##
## LEF for PtnCells ;
## created by Innovus v15.23-s045_1 on Mon Mar  9 14:37:24 2026
##

VERSION 5.8 ;

BUSBITCHARS "[]" ;
DIVIDERCHAR "/" ;

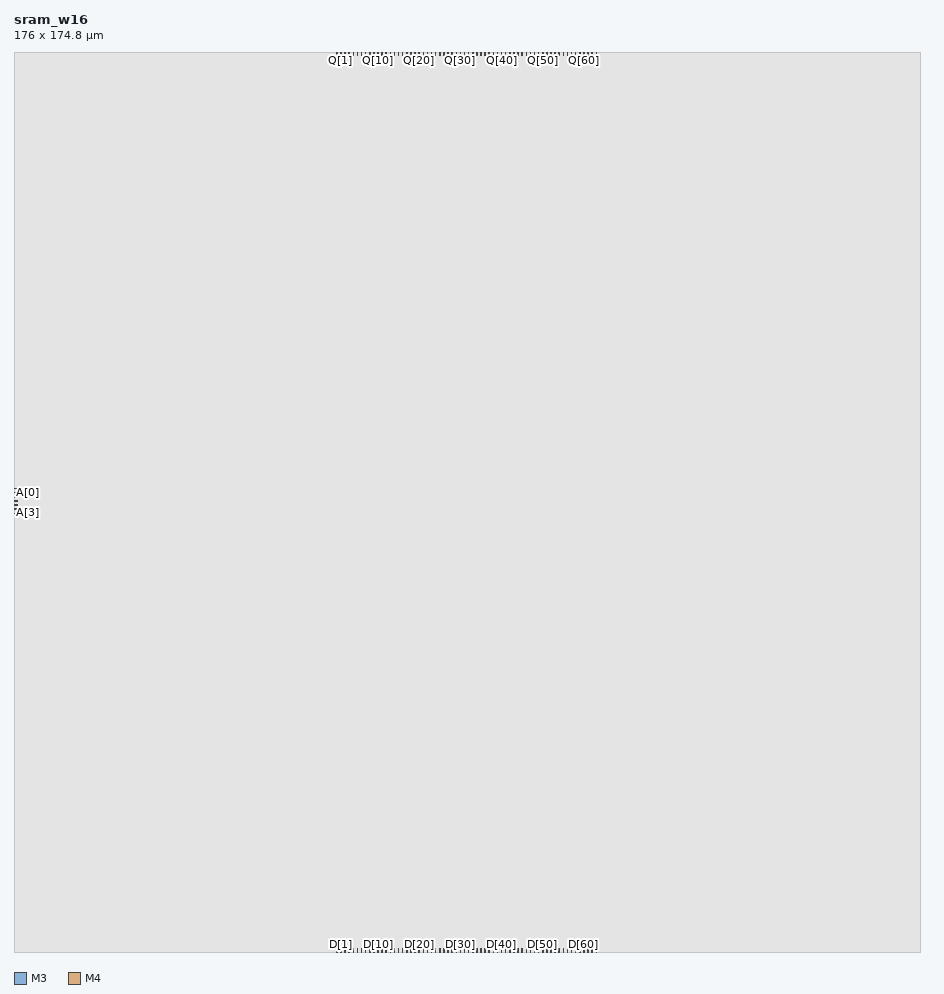
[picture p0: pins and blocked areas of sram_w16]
MACRO sram_w16
  CLASS BLOCK ;
  SIZE 176.0000 BY 174.8000 ;
  FOREIGN sram_w16 0.0000 0.0000 ;
  ORIGIN 0 0 ;
  SYMMETRY X Y R90 ;
  PIN CLK
    DIRECTION INPUT ;
    USE SIGNAL ;
    PORT
      LAYER M3 ;
        RECT 0.0000 85.1500 0.6000 85.2500 ;
    END
  END CLK
  PIN D[63]
    DIRECTION INPUT ;
    USE SIGNAL ;
    PORT
      LAYER M4 ;
        RECT 113.0500 0.0000 113.1500 0.6000 ;
    END
  END D[63]
  PIN D[62]
    DIRECTION INPUT ;
    USE SIGNAL ;
    PORT
      LAYER M4 ;
        RECT 112.2500 0.0000 112.3500 0.6000 ;
    END
  END D[62]
  PIN D[61]
    DIRECTION INPUT ;
    USE SIGNAL ;
    PORT
      LAYER M4 ;
        RECT 111.4500 0.0000 111.5500 0.6000 ;
    END
  END D[61]
  PIN D[60]
    DIRECTION INPUT ;
    USE SIGNAL ;
    PORT
      LAYER M4 ;
        RECT 110.6500 0.0000 110.7500 0.6000 ;
    END
  END D[60]
  PIN D[59]
    DIRECTION INPUT ;
    USE SIGNAL ;
    PORT
      LAYER M4 ;
        RECT 109.8500 0.0000 109.9500 0.6000 ;
    END
  END D[59]
  PIN D[58]
    DIRECTION INPUT ;
    USE SIGNAL ;
    PORT
      LAYER M4 ;
        RECT 109.0500 0.0000 109.1500 0.6000 ;
    END
  END D[58]
  PIN D[57]
    DIRECTION INPUT ;
    USE SIGNAL ;
    PORT
      LAYER M4 ;
        RECT 108.2500 0.0000 108.3500 0.6000 ;
    END
  END D[57]
  PIN D[56]
    DIRECTION INPUT ;
    USE SIGNAL ;
    PORT
      LAYER M4 ;
        RECT 107.4500 0.0000 107.5500 0.6000 ;
    END
  END D[56]
  PIN D[55]
    DIRECTION INPUT ;
    USE SIGNAL ;
    PORT
      LAYER M4 ;
        RECT 106.6500 0.0000 106.7500 0.6000 ;
    END
  END D[55]
  PIN D[54]
    DIRECTION INPUT ;
    USE SIGNAL ;
    PORT
      LAYER M4 ;
        RECT 105.8500 0.0000 105.9500 0.6000 ;
    END
  END D[54]
  PIN D[53]
    DIRECTION INPUT ;
    USE SIGNAL ;
    PORT
      LAYER M4 ;
        RECT 105.0500 0.0000 105.1500 0.6000 ;
    END
  END D[53]
  PIN D[52]
    DIRECTION INPUT ;
    USE SIGNAL ;
    PORT
      LAYER M4 ;
        RECT 104.2500 0.0000 104.3500 0.6000 ;
    END
  END D[52]
  PIN D[51]
    DIRECTION INPUT ;
    USE SIGNAL ;
    PORT
      LAYER M4 ;
        RECT 103.4500 0.0000 103.5500 0.6000 ;
    END
  END D[51]
  PIN D[50]
    DIRECTION INPUT ;
    USE SIGNAL ;
    PORT
      LAYER M4 ;
        RECT 102.6500 0.0000 102.7500 0.6000 ;
    END
  END D[50]
  PIN D[49]
    DIRECTION INPUT ;
    USE SIGNAL ;
    PORT
      LAYER M4 ;
        RECT 101.8500 0.0000 101.9500 0.6000 ;
    END
  END D[49]
  PIN D[48]
    DIRECTION INPUT ;
    USE SIGNAL ;
    PORT
      LAYER M4 ;
        RECT 101.0500 0.0000 101.1500 0.6000 ;
    END
  END D[48]
  PIN D[47]
    DIRECTION INPUT ;
    USE SIGNAL ;
    PORT
      LAYER M4 ;
        RECT 100.2500 0.0000 100.3500 0.6000 ;
    END
  END D[47]
  PIN D[46]
    DIRECTION INPUT ;
    USE SIGNAL ;
    PORT
      LAYER M4 ;
        RECT 99.4500 0.0000 99.5500 0.6000 ;
    END
  END D[46]
  PIN D[45]
    DIRECTION INPUT ;
    USE SIGNAL ;
    PORT
      LAYER M4 ;
        RECT 98.6500 0.0000 98.7500 0.6000 ;
    END
  END D[45]
  PIN D[44]
    DIRECTION INPUT ;
    USE SIGNAL ;
    PORT
      LAYER M4 ;
        RECT 97.8500 0.0000 97.9500 0.6000 ;
    END
  END D[44]
  PIN D[43]
    DIRECTION INPUT ;
    USE SIGNAL ;
    PORT
      LAYER M4 ;
        RECT 97.0500 0.0000 97.1500 0.6000 ;
    END
  END D[43]
  PIN D[42]
    DIRECTION INPUT ;
    USE SIGNAL ;
    PORT
      LAYER M4 ;
        RECT 96.2500 0.0000 96.3500 0.6000 ;
    END
  END D[42]
  PIN D[41]
    DIRECTION INPUT ;
    USE SIGNAL ;
    PORT
      LAYER M4 ;
        RECT 95.4500 0.0000 95.5500 0.6000 ;
    END
  END D[41]
  PIN D[40]
    DIRECTION INPUT ;
    USE SIGNAL ;
    PORT
      LAYER M4 ;
        RECT 94.6500 0.0000 94.7500 0.6000 ;
    END
  END D[40]
  PIN D[39]
    DIRECTION INPUT ;
    USE SIGNAL ;
    PORT
      LAYER M4 ;
        RECT 93.8500 0.0000 93.9500 0.6000 ;
    END
  END D[39]
  PIN D[38]
    DIRECTION INPUT ;
    USE SIGNAL ;
    PORT
      LAYER M4 ;
        RECT 93.0500 0.0000 93.1500 0.6000 ;
    END
  END D[38]
  PIN D[37]
    DIRECTION INPUT ;
    USE SIGNAL ;
    PORT
      LAYER M4 ;
        RECT 92.2500 0.0000 92.3500 0.6000 ;
    END
  END D[37]
  PIN D[36]
    DIRECTION INPUT ;
    USE SIGNAL ;
    PORT
      LAYER M4 ;
        RECT 91.4500 0.0000 91.5500 0.6000 ;
    END
  END D[36]
  PIN D[35]
    DIRECTION INPUT ;
    USE SIGNAL ;
    PORT
      LAYER M4 ;
        RECT 90.6500 0.0000 90.7500 0.6000 ;
    END
  END D[35]
  PIN D[34]
    DIRECTION INPUT ;
    USE SIGNAL ;
    PORT
      LAYER M4 ;
        RECT 89.8500 0.0000 89.9500 0.6000 ;
    END
  END D[34]
  PIN D[33]
    DIRECTION INPUT ;
    USE SIGNAL ;
    PORT
      LAYER M4 ;
        RECT 89.0500 0.0000 89.1500 0.6000 ;
    END
  END D[33]
  PIN D[32]
    DIRECTION INPUT ;
    USE SIGNAL ;
    PORT
      LAYER M4 ;
        RECT 88.2500 0.0000 88.3500 0.6000 ;
    END
  END D[32]
  PIN D[31]
    DIRECTION INPUT ;
    USE SIGNAL ;
    PORT
      LAYER M4 ;
        RECT 87.4500 0.0000 87.5500 0.6000 ;
    END
  END D[31]
  PIN D[30]
    DIRECTION INPUT ;
    USE SIGNAL ;
    PORT
      LAYER M4 ;
        RECT 86.6500 0.0000 86.7500 0.6000 ;
    END
  END D[30]
  PIN D[29]
    DIRECTION INPUT ;
    USE SIGNAL ;
    PORT
      LAYER M4 ;
        RECT 85.8500 0.0000 85.9500 0.6000 ;
    END
  END D[29]
  PIN D[28]
    DIRECTION INPUT ;
    USE SIGNAL ;
    PORT
      LAYER M4 ;
        RECT 85.0500 0.0000 85.1500 0.6000 ;
    END
  END D[28]
  PIN D[27]
    DIRECTION INPUT ;
    USE SIGNAL ;
    PORT
      LAYER M4 ;
        RECT 84.2500 0.0000 84.3500 0.6000 ;
    END
  END D[27]
  PIN D[26]
    DIRECTION INPUT ;
    USE SIGNAL ;
    PORT
      LAYER M4 ;
        RECT 83.4500 0.0000 83.5500 0.6000 ;
    END
  END D[26]
  PIN D[25]
    DIRECTION INPUT ;
    USE SIGNAL ;
    PORT
      LAYER M4 ;
        RECT 82.6500 0.0000 82.7500 0.6000 ;
    END
  END D[25]
  PIN D[24]
    DIRECTION INPUT ;
    USE SIGNAL ;
    PORT
      LAYER M4 ;
        RECT 81.8500 0.0000 81.9500 0.6000 ;
    END
  END D[24]
  PIN D[23]
    DIRECTION INPUT ;
    USE SIGNAL ;
    PORT
      LAYER M4 ;
        RECT 81.0500 0.0000 81.1500 0.6000 ;
    END
  END D[23]
  PIN D[22]
    DIRECTION INPUT ;
    USE SIGNAL ;
    PORT
      LAYER M4 ;
        RECT 80.2500 0.0000 80.3500 0.6000 ;
    END
  END D[22]
  PIN D[21]
    DIRECTION INPUT ;
    USE SIGNAL ;
    PORT
      LAYER M4 ;
        RECT 79.4500 0.0000 79.5500 0.6000 ;
    END
  END D[21]
  PIN D[20]
    DIRECTION INPUT ;
    USE SIGNAL ;
    PORT
      LAYER M4 ;
        RECT 78.6500 0.0000 78.7500 0.6000 ;
    END
  END D[20]
  PIN D[19]
    DIRECTION INPUT ;
    USE SIGNAL ;
    PORT
      LAYER M4 ;
        RECT 77.8500 0.0000 77.9500 0.6000 ;
    END
  END D[19]
  PIN D[18]
    DIRECTION INPUT ;
    USE SIGNAL ;
    PORT
      LAYER M4 ;
        RECT 77.0500 0.0000 77.1500 0.6000 ;
    END
  END D[18]
  PIN D[17]
    DIRECTION INPUT ;
    USE SIGNAL ;
    PORT
      LAYER M4 ;
        RECT 76.2500 0.0000 76.3500 0.6000 ;
    END
  END D[17]
  PIN D[16]
    DIRECTION INPUT ;
    USE SIGNAL ;
    PORT
      LAYER M4 ;
        RECT 75.4500 0.0000 75.5500 0.6000 ;
    END
  END D[16]
  PIN D[15]
    DIRECTION INPUT ;
    USE SIGNAL ;
    PORT
      LAYER M4 ;
        RECT 74.6500 0.0000 74.7500 0.6000 ;
    END
  END D[15]
  PIN D[14]
    DIRECTION INPUT ;
    USE SIGNAL ;
    PORT
      LAYER M4 ;
        RECT 73.8500 0.0000 73.9500 0.6000 ;
    END
  END D[14]
  PIN D[13]
    DIRECTION INPUT ;
    USE SIGNAL ;
    PORT
      LAYER M4 ;
        RECT 73.0500 0.0000 73.1500 0.6000 ;
    END
  END D[13]
  PIN D[12]
    DIRECTION INPUT ;
    USE SIGNAL ;
    PORT
      LAYER M4 ;
        RECT 72.2500 0.0000 72.3500 0.6000 ;
    END
  END D[12]
  PIN D[11]
    DIRECTION INPUT ;
    USE SIGNAL ;
    PORT
      LAYER M4 ;
        RECT 71.4500 0.0000 71.5500 0.6000 ;
    END
  END D[11]
  PIN D[10]
    DIRECTION INPUT ;
    USE SIGNAL ;
    PORT
      LAYER M4 ;
        RECT 70.6500 0.0000 70.7500 0.6000 ;
    END
  END D[10]
  PIN D[9]
    DIRECTION INPUT ;
    USE SIGNAL ;
    PORT
      LAYER M4 ;
        RECT 69.8500 0.0000 69.9500 0.6000 ;
    END
  END D[9]
  PIN D[8]
    DIRECTION INPUT ;
    USE SIGNAL ;
    PORT
      LAYER M4 ;
        RECT 69.0500 0.0000 69.1500 0.6000 ;
    END
  END D[8]
  PIN D[7]
    DIRECTION INPUT ;
    USE SIGNAL ;
    PORT
      LAYER M4 ;
        RECT 68.2500 0.0000 68.3500 0.6000 ;
    END
  END D[7]
  PIN D[6]
    DIRECTION INPUT ;
    USE SIGNAL ;
    PORT
      LAYER M4 ;
        RECT 67.4500 0.0000 67.5500 0.6000 ;
    END
  END D[6]
  PIN D[5]
    DIRECTION INPUT ;
    USE SIGNAL ;
    PORT
      LAYER M4 ;
        RECT 66.6500 0.0000 66.7500 0.6000 ;
    END
  END D[5]
  PIN D[4]
    DIRECTION INPUT ;
    USE SIGNAL ;
    PORT
      LAYER M4 ;
        RECT 65.8500 0.0000 65.9500 0.6000 ;
    END
  END D[4]
  PIN D[3]
    DIRECTION INPUT ;
    USE SIGNAL ;
    PORT
      LAYER M4 ;
        RECT 65.0500 0.0000 65.1500 0.6000 ;
    END
  END D[3]
  PIN D[2]
    DIRECTION INPUT ;
    USE SIGNAL ;
    PORT
      LAYER M4 ;
        RECT 64.2500 0.0000 64.3500 0.6000 ;
    END
  END D[2]
  PIN D[1]
    DIRECTION INPUT ;
    USE SIGNAL ;
    PORT
      LAYER M4 ;
        RECT 63.4500 0.0000 63.5500 0.6000 ;
    END
  END D[1]
  PIN D[0]
    DIRECTION INPUT ;
    USE SIGNAL ;
    PORT
      LAYER M4 ;
        RECT 62.6500 0.0000 62.7500 0.6000 ;
    END
  END D[0]
  PIN Q[63]
    DIRECTION OUTPUT ;
    USE SIGNAL ;
    PORT
      LAYER M4 ;
        RECT 113.0500 174.2000 113.1500 174.8000 ;
    END
  END Q[63]
  PIN Q[62]
    DIRECTION OUTPUT ;
    USE SIGNAL ;
    PORT
      LAYER M4 ;
        RECT 112.2500 174.2000 112.3500 174.8000 ;
    END
  END Q[62]
  PIN Q[61]
    DIRECTION OUTPUT ;
    USE SIGNAL ;
    PORT
      LAYER M4 ;
        RECT 111.4500 174.2000 111.5500 174.8000 ;
    END
  END Q[61]
  PIN Q[60]
    DIRECTION OUTPUT ;
    USE SIGNAL ;
    PORT
      LAYER M4 ;
        RECT 110.6500 174.2000 110.7500 174.8000 ;
    END
  END Q[60]
  PIN Q[59]
    DIRECTION OUTPUT ;
    USE SIGNAL ;
    PORT
      LAYER M4 ;
        RECT 109.8500 174.2000 109.9500 174.8000 ;
    END
  END Q[59]
  PIN Q[58]
    DIRECTION OUTPUT ;
    USE SIGNAL ;
    PORT
      LAYER M4 ;
        RECT 109.0500 174.2000 109.1500 174.8000 ;
    END
  END Q[58]
  PIN Q[57]
    DIRECTION OUTPUT ;
    USE SIGNAL ;
    PORT
      LAYER M4 ;
        RECT 108.2500 174.2000 108.3500 174.8000 ;
    END
  END Q[57]
  PIN Q[56]
    DIRECTION OUTPUT ;
    USE SIGNAL ;
    PORT
      LAYER M4 ;
        RECT 107.4500 174.2000 107.5500 174.8000 ;
    END
  END Q[56]
  PIN Q[55]
    DIRECTION OUTPUT ;
    USE SIGNAL ;
    PORT
      LAYER M4 ;
        RECT 106.6500 174.2000 106.7500 174.8000 ;
    END
  END Q[55]
  PIN Q[54]
    DIRECTION OUTPUT ;
    USE SIGNAL ;
    PORT
      LAYER M4 ;
        RECT 105.8500 174.2000 105.9500 174.8000 ;
    END
  END Q[54]
  PIN Q[53]
    DIRECTION OUTPUT ;
    USE SIGNAL ;
    PORT
      LAYER M4 ;
        RECT 105.0500 174.2000 105.1500 174.8000 ;
    END
  END Q[53]
  PIN Q[52]
    DIRECTION OUTPUT ;
    USE SIGNAL ;
    PORT
      LAYER M4 ;
        RECT 104.2500 174.2000 104.3500 174.8000 ;
    END
  END Q[52]
  PIN Q[51]
    DIRECTION OUTPUT ;
    USE SIGNAL ;
    PORT
      LAYER M4 ;
        RECT 103.4500 174.2000 103.5500 174.8000 ;
    END
  END Q[51]
  PIN Q[50]
    DIRECTION OUTPUT ;
    USE SIGNAL ;
    PORT
      LAYER M4 ;
        RECT 102.6500 174.2000 102.7500 174.8000 ;
    END
  END Q[50]
  PIN Q[49]
    DIRECTION OUTPUT ;
    USE SIGNAL ;
    PORT
      LAYER M4 ;
        RECT 101.8500 174.2000 101.9500 174.8000 ;
    END
  END Q[49]
  PIN Q[48]
    DIRECTION OUTPUT ;
    USE SIGNAL ;
    PORT
      LAYER M4 ;
        RECT 101.0500 174.2000 101.1500 174.8000 ;
    END
  END Q[48]
  PIN Q[47]
    DIRECTION OUTPUT ;
    USE SIGNAL ;
    PORT
      LAYER M4 ;
        RECT 100.2500 174.2000 100.3500 174.8000 ;
    END
  END Q[47]
  PIN Q[46]
    DIRECTION OUTPUT ;
    USE SIGNAL ;
    PORT
      LAYER M4 ;
        RECT 99.4500 174.2000 99.5500 174.8000 ;
    END
  END Q[46]
  PIN Q[45]
    DIRECTION OUTPUT ;
    USE SIGNAL ;
    PORT
      LAYER M4 ;
        RECT 98.6500 174.2000 98.7500 174.8000 ;
    END
  END Q[45]
  PIN Q[44]
    DIRECTION OUTPUT ;
    USE SIGNAL ;
    PORT
      LAYER M4 ;
        RECT 97.8500 174.2000 97.9500 174.8000 ;
    END
  END Q[44]
  PIN Q[43]
    DIRECTION OUTPUT ;
    USE SIGNAL ;
    PORT
      LAYER M4 ;
        RECT 97.0500 174.2000 97.1500 174.8000 ;
    END
  END Q[43]
  PIN Q[42]
    DIRECTION OUTPUT ;
    USE SIGNAL ;
    PORT
      LAYER M4 ;
        RECT 96.2500 174.2000 96.3500 174.8000 ;
    END
  END Q[42]
  PIN Q[41]
    DIRECTION OUTPUT ;
    USE SIGNAL ;
    PORT
      LAYER M4 ;
        RECT 95.4500 174.2000 95.5500 174.8000 ;
    END
  END Q[41]
  PIN Q[40]
    DIRECTION OUTPUT ;
    USE SIGNAL ;
    PORT
      LAYER M4 ;
        RECT 94.6500 174.2000 94.7500 174.8000 ;
    END
  END Q[40]
  PIN Q[39]
    DIRECTION OUTPUT ;
    USE SIGNAL ;
    PORT
      LAYER M4 ;
        RECT 93.8500 174.2000 93.9500 174.8000 ;
    END
  END Q[39]
  PIN Q[38]
    DIRECTION OUTPUT ;
    USE SIGNAL ;
    PORT
      LAYER M4 ;
        RECT 93.0500 174.2000 93.1500 174.8000 ;
    END
  END Q[38]
  PIN Q[37]
    DIRECTION OUTPUT ;
    USE SIGNAL ;
    PORT
      LAYER M4 ;
        RECT 92.2500 174.2000 92.3500 174.8000 ;
    END
  END Q[37]
  PIN Q[36]
    DIRECTION OUTPUT ;
    USE SIGNAL ;
    PORT
      LAYER M4 ;
        RECT 91.4500 174.2000 91.5500 174.8000 ;
    END
  END Q[36]
  PIN Q[35]
    DIRECTION OUTPUT ;
    USE SIGNAL ;
    PORT
      LAYER M4 ;
        RECT 90.6500 174.2000 90.7500 174.8000 ;
    END
  END Q[35]
  PIN Q[34]
    DIRECTION OUTPUT ;
    USE SIGNAL ;
    PORT
      LAYER M4 ;
        RECT 89.8500 174.2000 89.9500 174.8000 ;
    END
  END Q[34]
  PIN Q[33]
    DIRECTION OUTPUT ;
    USE SIGNAL ;
    PORT
      LAYER M4 ;
        RECT 89.0500 174.2000 89.1500 174.8000 ;
    END
  END Q[33]
  PIN Q[32]
    DIRECTION OUTPUT ;
    USE SIGNAL ;
    PORT
      LAYER M4 ;
        RECT 88.2500 174.2000 88.3500 174.8000 ;
    END
  END Q[32]
  PIN Q[31]
    DIRECTION OUTPUT ;
    USE SIGNAL ;
    PORT
      LAYER M4 ;
        RECT 87.4500 174.2000 87.5500 174.8000 ;
    END
  END Q[31]
  PIN Q[30]
    DIRECTION OUTPUT ;
    USE SIGNAL ;
    PORT
      LAYER M4 ;
        RECT 86.6500 174.2000 86.7500 174.8000 ;
    END
  END Q[30]
  PIN Q[29]
    DIRECTION OUTPUT ;
    USE SIGNAL ;
    PORT
      LAYER M4 ;
        RECT 85.8500 174.2000 85.9500 174.8000 ;
    END
  END Q[29]
  PIN Q[28]
    DIRECTION OUTPUT ;
    USE SIGNAL ;
    PORT
      LAYER M4 ;
        RECT 85.0500 174.2000 85.1500 174.8000 ;
    END
  END Q[28]
  PIN Q[27]
    DIRECTION OUTPUT ;
    USE SIGNAL ;
    PORT
      LAYER M4 ;
        RECT 84.2500 174.2000 84.3500 174.8000 ;
    END
  END Q[27]
  PIN Q[26]
    DIRECTION OUTPUT ;
    USE SIGNAL ;
    PORT
      LAYER M4 ;
        RECT 83.4500 174.2000 83.5500 174.8000 ;
    END
  END Q[26]
  PIN Q[25]
    DIRECTION OUTPUT ;
    USE SIGNAL ;
    PORT
      LAYER M4 ;
        RECT 82.6500 174.2000 82.7500 174.8000 ;
    END
  END Q[25]
  PIN Q[24]
    DIRECTION OUTPUT ;
    USE SIGNAL ;
    PORT
      LAYER M4 ;
        RECT 81.8500 174.2000 81.9500 174.8000 ;
    END
  END Q[24]
  PIN Q[23]
    DIRECTION OUTPUT ;
    USE SIGNAL ;
    PORT
      LAYER M4 ;
        RECT 81.0500 174.2000 81.1500 174.8000 ;
    END
  END Q[23]
  PIN Q[22]
    DIRECTION OUTPUT ;
    USE SIGNAL ;
    PORT
      LAYER M4 ;
        RECT 80.2500 174.2000 80.3500 174.8000 ;
    END
  END Q[22]
  PIN Q[21]
    DIRECTION OUTPUT ;
    USE SIGNAL ;
    PORT
      LAYER M4 ;
        RECT 79.4500 174.2000 79.5500 174.8000 ;
    END
  END Q[21]
  PIN Q[20]
    DIRECTION OUTPUT ;
    USE SIGNAL ;
    PORT
      LAYER M4 ;
        RECT 78.6500 174.2000 78.7500 174.8000 ;
    END
  END Q[20]
  PIN Q[19]
    DIRECTION OUTPUT ;
    USE SIGNAL ;
    PORT
      LAYER M4 ;
        RECT 77.8500 174.2000 77.9500 174.8000 ;
    END
  END Q[19]
  PIN Q[18]
    DIRECTION OUTPUT ;
    USE SIGNAL ;
    PORT
      LAYER M4 ;
        RECT 77.0500 174.2000 77.1500 174.8000 ;
    END
  END Q[18]
  PIN Q[17]
    DIRECTION OUTPUT ;
    USE SIGNAL ;
    PORT
      LAYER M4 ;
        RECT 76.2500 174.2000 76.3500 174.8000 ;
    END
  END Q[17]
  PIN Q[16]
    DIRECTION OUTPUT ;
    USE SIGNAL ;
    PORT
      LAYER M4 ;
        RECT 75.4500 174.2000 75.5500 174.8000 ;
    END
  END Q[16]
  PIN Q[15]
    DIRECTION OUTPUT ;
    USE SIGNAL ;
    PORT
      LAYER M4 ;
        RECT 74.6500 174.2000 74.7500 174.8000 ;
    END
  END Q[15]
  PIN Q[14]
    DIRECTION OUTPUT ;
    USE SIGNAL ;
    PORT
      LAYER M4 ;
        RECT 73.8500 174.2000 73.9500 174.8000 ;
    END
  END Q[14]
  PIN Q[13]
    DIRECTION OUTPUT ;
    USE SIGNAL ;
    PORT
      LAYER M4 ;
        RECT 73.0500 174.2000 73.1500 174.8000 ;
    END
  END Q[13]
  PIN Q[12]
    DIRECTION OUTPUT ;
    USE SIGNAL ;
    PORT
      LAYER M4 ;
        RECT 72.2500 174.2000 72.3500 174.8000 ;
    END
  END Q[12]
  PIN Q[11]
    DIRECTION OUTPUT ;
    USE SIGNAL ;
    PORT
      LAYER M4 ;
        RECT 71.4500 174.2000 71.5500 174.8000 ;
    END
  END Q[11]
  PIN Q[10]
    DIRECTION OUTPUT ;
    USE SIGNAL ;
    PORT
      LAYER M4 ;
        RECT 70.6500 174.2000 70.7500 174.8000 ;
    END
  END Q[10]
  PIN Q[9]
    DIRECTION OUTPUT ;
    USE SIGNAL ;
    PORT
      LAYER M4 ;
        RECT 69.8500 174.2000 69.9500 174.8000 ;
    END
  END Q[9]
  PIN Q[8]
    DIRECTION OUTPUT ;
    USE SIGNAL ;
    PORT
      LAYER M4 ;
        RECT 69.0500 174.2000 69.1500 174.8000 ;
    END
  END Q[8]
  PIN Q[7]
    DIRECTION OUTPUT ;
    USE SIGNAL ;
    PORT
      LAYER M4 ;
        RECT 68.2500 174.2000 68.3500 174.8000 ;
    END
  END Q[7]
  PIN Q[6]
    DIRECTION OUTPUT ;
    USE SIGNAL ;
    PORT
      LAYER M4 ;
        RECT 67.4500 174.2000 67.5500 174.8000 ;
    END
  END Q[6]
  PIN Q[5]
    DIRECTION OUTPUT ;
    USE SIGNAL ;
    PORT
      LAYER M4 ;
        RECT 66.6500 174.2000 66.7500 174.8000 ;
    END
  END Q[5]
  PIN Q[4]
    DIRECTION OUTPUT ;
    USE SIGNAL ;
    PORT
      LAYER M4 ;
        RECT 65.8500 174.2000 65.9500 174.8000 ;
    END
  END Q[4]
  PIN Q[3]
    DIRECTION OUTPUT ;
    USE SIGNAL ;
    PORT
      LAYER M4 ;
        RECT 65.0500 174.2000 65.1500 174.8000 ;
    END
  END Q[3]
  PIN Q[2]
    DIRECTION OUTPUT ;
    USE SIGNAL ;
    PORT
      LAYER M4 ;
        RECT 64.2500 174.2000 64.3500 174.8000 ;
    END
  END Q[2]
  PIN Q[1]
    DIRECTION OUTPUT ;
    USE SIGNAL ;
    PORT
      LAYER M4 ;
        RECT 63.4500 174.2000 63.5500 174.8000 ;
    END
  END Q[1]
  PIN Q[0]
    DIRECTION OUTPUT ;
    USE SIGNAL ;
    PORT
      LAYER M4 ;
        RECT 62.6500 174.2000 62.7500 174.8000 ;
    END
  END Q[0]
  PIN CEN
    DIRECTION INPUT ;
    USE SIGNAL ;
    PORT
      LAYER M3 ;
        RECT 0.0000 85.9500 0.6000 86.0500 ;
    END
  END CEN
  PIN WEN
    DIRECTION INPUT ;
    USE SIGNAL ;
    PORT
      LAYER M3 ;
        RECT 0.0000 89.9500 0.6000 90.0500 ;
    END
  END WEN
  PIN A[3]
    DIRECTION INPUT ;
    USE SIGNAL ;
    PORT
      LAYER M3 ;
        RECT 0.0000 86.7500 0.6000 86.8500 ;
    END
  END A[3]
  PIN A[2]
    DIRECTION INPUT ;
    USE SIGNAL ;
    PORT
      LAYER M3 ;
        RECT 0.0000 87.5500 0.6000 87.6500 ;
    END
  END A[2]
  PIN A[1]
    DIRECTION INPUT ;
    USE SIGNAL ;
    PORT
      LAYER M3 ;
        RECT 0.0000 88.3500 0.6000 88.4500 ;
    END
  END A[1]
  PIN A[0]
    DIRECTION INPUT ;
    USE SIGNAL ;
    PORT
      LAYER M3 ;
        RECT 0.0000 89.1500 0.6000 89.2500 ;
    END
  END A[0]
  OBS
    LAYER M1 ;
      RECT 0.0000 0.0000 176.0000 174.8000 ;
    LAYER M2 ;
      RECT 0.0000 0.0000 176.0000 174.8000 ;
    LAYER M3 ;
      RECT 0.0000 90.1500 176.0000 174.8000 ;
      RECT 0.7000 89.8500 176.0000 90.1500 ;
      RECT 0.0000 89.3500 176.0000 89.8500 ;
      RECT 0.7000 89.0500 176.0000 89.3500 ;
      RECT 0.0000 88.5500 176.0000 89.0500 ;
      RECT 0.7000 88.2500 176.0000 88.5500 ;
      RECT 0.0000 87.7500 176.0000 88.2500 ;
      RECT 0.7000 87.4500 176.0000 87.7500 ;
      RECT 0.0000 86.9500 176.0000 87.4500 ;
      RECT 0.7000 86.6500 176.0000 86.9500 ;
      RECT 0.0000 86.1500 176.0000 86.6500 ;
      RECT 0.7000 85.8500 176.0000 86.1500 ;
      RECT 0.0000 85.3500 176.0000 85.8500 ;
      RECT 0.7000 85.0500 176.0000 85.3500 ;
      RECT 0.0000 0.0000 176.0000 85.0500 ;
    LAYER M4 ;
      RECT 113.2500 174.1000 176.0000 174.8000 ;
      RECT 112.4500 174.1000 112.9500 174.8000 ;
      RECT 111.6500 174.1000 112.1500 174.8000 ;
      RECT 110.8500 174.1000 111.3500 174.8000 ;
      RECT 110.0500 174.1000 110.5500 174.8000 ;
      RECT 109.2500 174.1000 109.7500 174.8000 ;
      RECT 108.4500 174.1000 108.9500 174.8000 ;
      RECT 107.6500 174.1000 108.1500 174.8000 ;
      RECT 106.8500 174.1000 107.3500 174.8000 ;
      RECT 106.0500 174.1000 106.5500 174.8000 ;
      RECT 105.2500 174.1000 105.7500 174.8000 ;
      RECT 104.4500 174.1000 104.9500 174.8000 ;
      RECT 103.6500 174.1000 104.1500 174.8000 ;
      RECT 102.8500 174.1000 103.3500 174.8000 ;
      RECT 102.0500 174.1000 102.5500 174.8000 ;
      RECT 101.2500 174.1000 101.7500 174.8000 ;
      RECT 100.4500 174.1000 100.9500 174.8000 ;
      RECT 99.6500 174.1000 100.1500 174.8000 ;
      RECT 98.8500 174.1000 99.3500 174.8000 ;
      RECT 98.0500 174.1000 98.5500 174.8000 ;
      RECT 97.2500 174.1000 97.7500 174.8000 ;
      RECT 96.4500 174.1000 96.9500 174.8000 ;
      RECT 95.6500 174.1000 96.1500 174.8000 ;
      RECT 94.8500 174.1000 95.3500 174.8000 ;
      RECT 94.0500 174.1000 94.5500 174.8000 ;
      RECT 93.2500 174.1000 93.7500 174.8000 ;
      RECT 92.4500 174.1000 92.9500 174.8000 ;
      RECT 91.6500 174.1000 92.1500 174.8000 ;
      RECT 90.8500 174.1000 91.3500 174.8000 ;
      RECT 90.0500 174.1000 90.5500 174.8000 ;
      RECT 89.2500 174.1000 89.7500 174.8000 ;
      RECT 88.4500 174.1000 88.9500 174.8000 ;
      RECT 87.6500 174.1000 88.1500 174.8000 ;
      RECT 86.8500 174.1000 87.3500 174.8000 ;
      RECT 86.0500 174.1000 86.5500 174.8000 ;
      RECT 85.2500 174.1000 85.7500 174.8000 ;
      RECT 84.4500 174.1000 84.9500 174.8000 ;
      RECT 83.6500 174.1000 84.1500 174.8000 ;
      RECT 82.8500 174.1000 83.3500 174.8000 ;
      RECT 82.0500 174.1000 82.5500 174.8000 ;
      RECT 81.2500 174.1000 81.7500 174.8000 ;
      RECT 80.4500 174.1000 80.9500 174.8000 ;
      RECT 79.6500 174.1000 80.1500 174.8000 ;
      RECT 78.8500 174.1000 79.3500 174.8000 ;
      RECT 78.0500 174.1000 78.5500 174.8000 ;
      RECT 77.2500 174.1000 77.7500 174.8000 ;
      RECT 76.4500 174.1000 76.9500 174.8000 ;
      RECT 75.6500 174.1000 76.1500 174.8000 ;
      RECT 74.8500 174.1000 75.3500 174.8000 ;
      RECT 74.0500 174.1000 74.5500 174.8000 ;
      RECT 73.2500 174.1000 73.7500 174.8000 ;
      RECT 72.4500 174.1000 72.9500 174.8000 ;
      RECT 71.6500 174.1000 72.1500 174.8000 ;
      RECT 70.8500 174.1000 71.3500 174.8000 ;
      RECT 70.0500 174.1000 70.5500 174.8000 ;
      RECT 69.2500 174.1000 69.7500 174.8000 ;
      RECT 68.4500 174.1000 68.9500 174.8000 ;
      RECT 67.6500 174.1000 68.1500 174.8000 ;
      RECT 66.8500 174.1000 67.3500 174.8000 ;
      RECT 66.0500 174.1000 66.5500 174.8000 ;
      RECT 65.2500 174.1000 65.7500 174.8000 ;
      RECT 64.4500 174.1000 64.9500 174.8000 ;
      RECT 63.6500 174.1000 64.1500 174.8000 ;
      RECT 62.8500 174.1000 63.3500 174.8000 ;
      RECT 0.0000 174.1000 62.5500 174.8000 ;
      RECT 0.0000 0.7000 176.0000 174.1000 ;
      RECT 113.2500 0.0000 176.0000 0.7000 ;
      RECT 112.4500 0.0000 112.9500 0.7000 ;
      RECT 111.6500 0.0000 112.1500 0.7000 ;
      RECT 110.8500 0.0000 111.3500 0.7000 ;
      RECT 110.0500 0.0000 110.5500 0.7000 ;
      RECT 109.2500 0.0000 109.7500 0.7000 ;
      RECT 108.4500 0.0000 108.9500 0.7000 ;
      RECT 107.6500 0.0000 108.1500 0.7000 ;
      RECT 106.8500 0.0000 107.3500 0.7000 ;
      RECT 106.0500 0.0000 106.5500 0.7000 ;
      RECT 105.2500 0.0000 105.7500 0.7000 ;
      RECT 104.4500 0.0000 104.9500 0.7000 ;
      RECT 103.6500 0.0000 104.1500 0.7000 ;
      RECT 102.8500 0.0000 103.3500 0.7000 ;
      RECT 102.0500 0.0000 102.5500 0.7000 ;
      RECT 101.2500 0.0000 101.7500 0.7000 ;
      RECT 100.4500 0.0000 100.9500 0.7000 ;
      RECT 99.6500 0.0000 100.1500 0.7000 ;
      RECT 98.8500 0.0000 99.3500 0.7000 ;
      RECT 98.0500 0.0000 98.5500 0.7000 ;
      RECT 97.2500 0.0000 97.7500 0.7000 ;
      RECT 96.4500 0.0000 96.9500 0.7000 ;
      RECT 95.6500 0.0000 96.1500 0.7000 ;
      RECT 94.8500 0.0000 95.3500 0.7000 ;
      RECT 94.0500 0.0000 94.5500 0.7000 ;
      RECT 93.2500 0.0000 93.7500 0.7000 ;
      RECT 92.4500 0.0000 92.9500 0.7000 ;
      RECT 91.6500 0.0000 92.1500 0.7000 ;
      RECT 90.8500 0.0000 91.3500 0.7000 ;
      RECT 90.0500 0.0000 90.5500 0.7000 ;
      RECT 89.2500 0.0000 89.7500 0.7000 ;
      RECT 88.4500 0.0000 88.9500 0.7000 ;
      RECT 87.6500 0.0000 88.1500 0.7000 ;
      RECT 86.8500 0.0000 87.3500 0.7000 ;
      RECT 86.0500 0.0000 86.5500 0.7000 ;
      RECT 85.2500 0.0000 85.7500 0.7000 ;
      RECT 84.4500 0.0000 84.9500 0.7000 ;
      RECT 83.6500 0.0000 84.1500 0.7000 ;
      RECT 82.8500 0.0000 83.3500 0.7000 ;
      RECT 82.0500 0.0000 82.5500 0.7000 ;
      RECT 81.2500 0.0000 81.7500 0.7000 ;
      RECT 80.4500 0.0000 80.9500 0.7000 ;
      RECT 79.6500 0.0000 80.1500 0.7000 ;
      RECT 78.8500 0.0000 79.3500 0.7000 ;
      RECT 78.0500 0.0000 78.5500 0.7000 ;
      RECT 77.2500 0.0000 77.7500 0.7000 ;
      RECT 76.4500 0.0000 76.9500 0.7000 ;
      RECT 75.6500 0.0000 76.1500 0.7000 ;
      RECT 74.8500 0.0000 75.3500 0.7000 ;
      RECT 74.0500 0.0000 74.5500 0.7000 ;
      RECT 73.2500 0.0000 73.7500 0.7000 ;
      RECT 72.4500 0.0000 72.9500 0.7000 ;
      RECT 71.6500 0.0000 72.1500 0.7000 ;
      RECT 70.8500 0.0000 71.3500 0.7000 ;
      RECT 70.0500 0.0000 70.5500 0.7000 ;
      RECT 69.2500 0.0000 69.7500 0.7000 ;
      RECT 68.4500 0.0000 68.9500 0.7000 ;
      RECT 67.6500 0.0000 68.1500 0.7000 ;
      RECT 66.8500 0.0000 67.3500 0.7000 ;
      RECT 66.0500 0.0000 66.5500 0.7000 ;
      RECT 65.2500 0.0000 65.7500 0.7000 ;
      RECT 64.4500 0.0000 64.9500 0.7000 ;
      RECT 63.6500 0.0000 64.1500 0.7000 ;
      RECT 62.8500 0.0000 63.3500 0.7000 ;
      RECT 0.0000 0.0000 62.5500 0.7000 ;
    LAYER M5 ;
      RECT 0.0000 0.0000 176.0000 174.8000 ;
    LAYER M6 ;
      RECT 0.0000 0.0000 176.0000 174.8000 ;
    LAYER M7 ;
      RECT 0.0000 0.0000 176.0000 174.8000 ;
    LAYER M8 ;
      RECT 0.0000 0.0000 176.0000 174.8000 ;
  END
END sram_w16

END LIBRARY
